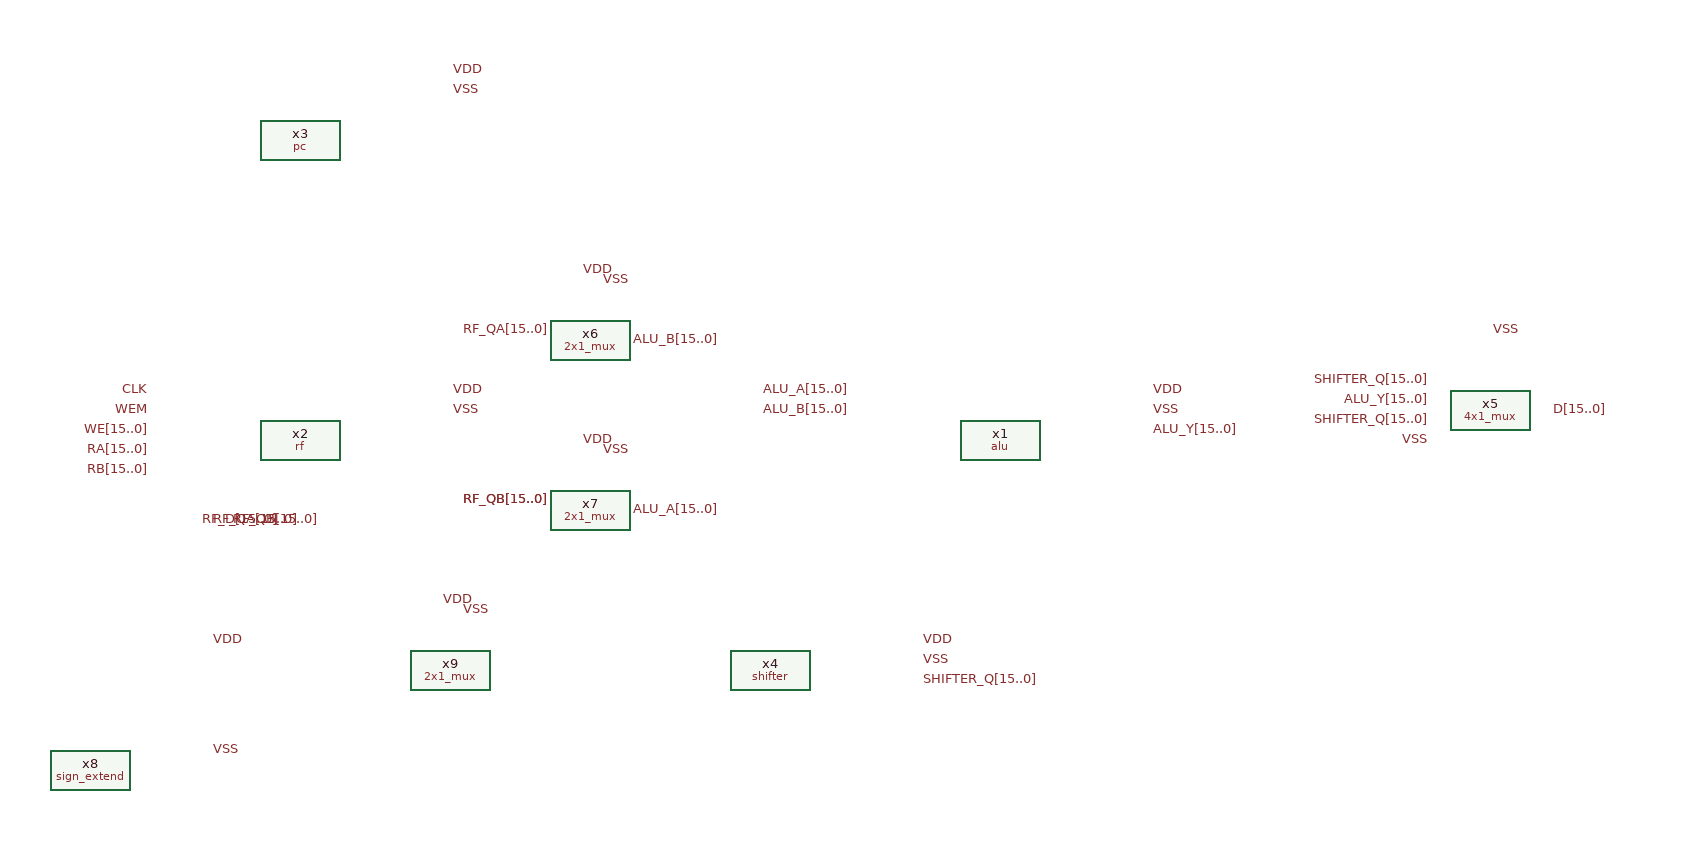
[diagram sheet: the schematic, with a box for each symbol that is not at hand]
v {xschem version=3.4.7 file_version=1.2}
G {}
K {}
V {}
S {}
E {}
C {/foss/designs/engn1600-team1/CAD4/alu.sym} 530 -70 0 0 {name=x1}
C {/foss/designs/engn1600-team1/CAD3/rf.sym} -170 -70 0 0 {name=x2}
C {/foss/designs/engn1600-team1/CAD6/pc.sym} -170 -370 0 0 {name=x3}
C {/foss/designs/engn1600-team1/CAD5/shifter.sym} 300 160 0 0 {name=x4}
C {lab_pin.sym} -20 -440 0 1 {name=p1 sig_type=std_logic lab=VDD
}
C {lab_pin.sym} 680 -120 0 1 {name=p2 sig_type=std_logic lab=VDD
}
C {lab_pin.sym} -20 -120 0 1 {name=p3 sig_type=std_logic lab=VDD
}
C {lab_pin.sym} 450 130 0 1 {name=p4 sig_type=std_logic lab=VDD
}
C {lab_pin.sym} -20 -420 0 1 {name=p5 sig_type=std_logic lab=VSS

}
C {lab_pin.sym} -20 -100 0 1 {name=p6 sig_type=std_logic lab=VSS

}
C {lab_pin.sym} 680 -100 0 1 {name=p7 sig_type=std_logic lab=VSS

}
C {lab_pin.sym} 450 150 0 1 {name=p8 sig_type=std_logic lab=VSS

}
C {lab_pin.sym} -320 -80 0 0 {name=p9 sig_type=std_logic lab=WE[15..0]}
C {lab_pin.sym} -320 -100 0 0 {name=p10 sig_type=std_logic lab=WEM
}
C {lab_pin.sym} -320 -60 0 0 {name=p11 sig_type=std_logic lab=RA[15..0]}
C {lab_pin.sym} -320 -40 0 0 {name=p12 sig_type=std_logic lab=RB[15..0]}
C {lab_pin.sym} -320 -120 0 0 {name=p13 sig_type=std_logic lab=CLK
}
C {lab_pin.sym} -150 10 3 0 {name=p14 sig_type=std_logic lab=RF_QB[15..0]
}
C {lab_pin.sym} -170 10 3 0 {name=p15 sig_type=std_logic lab=RF_QA[15..0]
}
C {lab_pin.sym} -190 10 3 0 {name=p16 sig_type=std_logic lab=RF_D[15..0]
}
C {/foss/designs/engn1600-team1/CAD4/4x1_mux.sym} 1020 -100 0 0 {name=x5}
C {lab_pin.sym} 1020 -180 0 1 {name=p17 sig_type=std_logic lab=VSS

}
C {lab_pin.sym} 960 -70 0 0 {name=p18 sig_type=std_logic lab=VSS

}
C {lab_pin.sym} 680 -80 0 1 {name=p19 sig_type=std_logic lab=ALU_Y[15..0]

}
C {lab_pin.sym} 960 -110 0 0 {name=p20 sig_type=std_logic lab=ALU_Y[15..0]

}
C {lab_pin.sym} 960 -130 0 0 {name=p21 sig_type=std_logic lab=SHIFTER_Q[15..0]

}
C {lab_pin.sym} 960 -90 0 0 {name=p22 sig_type=std_logic lab=SHIFTER_Q[15..0]

}
C {/foss/designs/engn1600-team1/CAD6/2x1_mux.sym} 120 -170 0 0 {name=x6}
C {/foss/designs/engn1600-team1/CAD6/2x1_mux.sym} 120 0 0 0 {name=x7}
C {lab_pin.sym} 80 -10 0 0 {name=p23 sig_type=std_logic lab=RF_QB[15..0]
}
C {lab_pin.sym} 80 -10 0 0 {name=p24 sig_type=std_logic lab=RF_QB[15..0]
}
C {lab_pin.sym} 80 -180 0 0 {name=p25 sig_type=std_logic lab=RF_QA[15..0]
}
C {lab_pin.sym} 160 0 0 1 {name=p26 sig_type=std_logic lab=ALU_A[15..0]

}
C {lab_pin.sym} 160 -170 0 1 {name=p27 sig_type=std_logic lab=ALU_B[15..0]

}
C {lab_pin.sym} 380 -100 0 0 {name=p28 sig_type=std_logic lab=ALU_B[15..0]

}
C {lab_pin.sym} 380 -120 0 0 {name=p29 sig_type=std_logic lab=ALU_A[15..0]

}
C {lab_pin.sym} 110 -240 0 1 {name=p30 sig_type=std_logic lab=VDD
}
C {lab_pin.sym} 110 -70 0 1 {name=p31 sig_type=std_logic lab=VDD
}
C {lab_pin.sym} 130 -230 0 1 {name=p32 sig_type=std_logic lab=VSS

}
C {lab_pin.sym} 130 -60 0 1 {name=p33 sig_type=std_logic lab=VSS

}
C {lab_pin.sym} 1080 -100 0 1 {name=p34 sig_type=std_logic lab=D[15..0]

}
C {lab_pin.sym} 450 170 0 1 {name=p35 sig_type=std_logic lab=SHIFTER_Q[15..0]

}
C {/foss/designs/engn1600-team1/CAD6/sign_extend.sym} -380 260 0 0 {name=x8}
C {/foss/designs/engn1600-team1/CAD6/2x1_mux.sym} -20 160 0 0 {name=x9}
C {lab_pin.sym} -30 90 0 1 {name=p36 sig_type=std_logic lab=VDD
}
C {lab_pin.sym} -10 100 0 1 {name=p37 sig_type=std_logic lab=VSS

}
C {lab_pin.sym} -260 240 0 1 {name=p38 sig_type=std_logic lab=VSS

}
C {lab_pin.sym} -260 130 0 1 {name=p39 sig_type=std_logic lab=VDD
}
